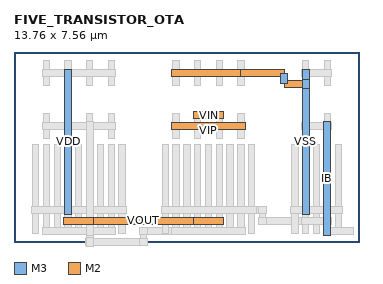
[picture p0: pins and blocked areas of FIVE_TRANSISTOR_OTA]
MACRO FIVE_TRANSISTOR_OTA
  ORIGIN 0 0 ;
  FOREIGN FIVE_TRANSISTOR_OTA 0 0 ;
  SIZE 13.76 BY 7.56 ;
  PIN IB
    DIRECTION INOUT ;
    USE SIGNAL ;
    PORT 
      LAYER M3 ;
        RECT 12.33 0.26 12.61 4.78 ;
    END
  END IB
  PIN VSS
    DIRECTION INOUT ;
    USE SIGNAL ;
    PORT 
      LAYER M2 ;
        RECT 6.28 6.58 9.2 6.86 ;
      LAYER M3 ;
        RECT 11.47 1.1 11.75 6.88 ;
      LAYER M2 ;
        RECT 9.03 6.58 10.75 6.86 ;
      LAYER M3 ;
        RECT 10.61 6.3 10.89 6.72 ;
      LAYER M2 ;
        RECT 10.75 6.16 11.61 6.44 ;
      LAYER M3 ;
        RECT 11.47 6.115 11.75 6.485 ;
    END
  END VSS
  PIN VOUT
    DIRECTION INOUT ;
    USE SIGNAL ;
    PORT 
      LAYER M2 ;
        RECT 1.98 0.7 3.18 0.98 ;
      LAYER M2 ;
        RECT 7.14 0.7 8.34 0.98 ;
      LAYER M2 ;
        RECT 3.01 0.7 7.31 0.98 ;
    END
  END VOUT
  PIN VDD
    DIRECTION INOUT ;
    USE SIGNAL ;
    PORT 
      LAYER M3 ;
        RECT 2.01 1.1 2.29 6.88 ;
    END
  END VDD
  PIN VIP
    DIRECTION INOUT ;
    USE SIGNAL ;
    PORT 
      LAYER M2 ;
        RECT 6.28 4.48 9.2 4.76 ;
    END
  END VIP
  PIN VIN
    DIRECTION INOUT ;
    USE SIGNAL ;
    PORT 
      LAYER M2 ;
        RECT 7.14 4.9 8.34 5.18 ;
    END
  END VIN
  OBS 
  LAYER M2 ;
        RECT 5.85 1.12 9.63 1.4 ;
  LAYER M2 ;
        RECT 11.44 0.7 12.64 0.98 ;
  LAYER M2 ;
        RECT 9.46 1.12 9.89 1.4 ;
  LAYER M1 ;
        RECT 9.765 0.84 10.015 1.26 ;
  LAYER M2 ;
        RECT 9.89 0.7 11.61 0.98 ;
  LAYER M1 ;
        RECT 9.765 0.755 10.015 0.925 ;
  LAYER M2 ;
        RECT 9.72 0.7 10.06 0.98 ;
  LAYER M1 ;
        RECT 9.765 1.175 10.015 1.345 ;
  LAYER M2 ;
        RECT 9.72 1.12 10.06 1.4 ;
  LAYER M1 ;
        RECT 9.765 0.755 10.015 0.925 ;
  LAYER M2 ;
        RECT 9.72 0.7 10.06 0.98 ;
  LAYER M1 ;
        RECT 9.765 1.175 10.015 1.345 ;
  LAYER M2 ;
        RECT 9.72 1.12 10.06 1.4 ;
  LAYER M3 ;
        RECT 2.87 0.26 3.15 4.78 ;
  LAYER M2 ;
        RECT 6.28 0.28 9.2 0.56 ;
  LAYER M3 ;
        RECT 2.87 0 3.15 0.42 ;
  LAYER M2 ;
        RECT 3.01 -0.14 5.16 0.14 ;
  LAYER M1 ;
        RECT 5.035 0 5.285 0.42 ;
  LAYER M2 ;
        RECT 5.16 0.28 6.45 0.56 ;
  LAYER M1 ;
        RECT 5.035 -0.085 5.285 0.085 ;
  LAYER M2 ;
        RECT 4.99 -0.14 5.33 0.14 ;
  LAYER M1 ;
        RECT 5.035 0.335 5.285 0.505 ;
  LAYER M2 ;
        RECT 4.99 0.28 5.33 0.56 ;
  LAYER M2 ;
        RECT 2.85 -0.14 3.17 0.14 ;
  LAYER M3 ;
        RECT 2.87 -0.16 3.15 0.16 ;
  LAYER M1 ;
        RECT 5.035 -0.085 5.285 0.085 ;
  LAYER M2 ;
        RECT 4.99 -0.14 5.33 0.14 ;
  LAYER M1 ;
        RECT 5.035 0.335 5.285 0.505 ;
  LAYER M2 ;
        RECT 4.99 0.28 5.33 0.56 ;
  LAYER M2 ;
        RECT 2.85 -0.14 3.17 0.14 ;
  LAYER M3 ;
        RECT 2.87 -0.16 3.15 0.16 ;
  LAYER M1 ;
        RECT 12.345 0.335 12.595 3.865 ;
  LAYER M1 ;
        RECT 12.345 4.115 12.595 5.125 ;
  LAYER M1 ;
        RECT 12.345 6.215 12.595 7.225 ;
  LAYER M1 ;
        RECT 12.775 0.335 13.025 3.865 ;
  LAYER M1 ;
        RECT 11.915 0.335 12.165 3.865 ;
  LAYER M1 ;
        RECT 11.485 0.335 11.735 3.865 ;
  LAYER M1 ;
        RECT 11.485 4.115 11.735 5.125 ;
  LAYER M1 ;
        RECT 11.485 6.215 11.735 7.225 ;
  LAYER M1 ;
        RECT 11.055 0.335 11.305 3.865 ;
  LAYER M2 ;
        RECT 12.3 0.28 13.5 0.56 ;
  LAYER M2 ;
        RECT 11.44 4.48 12.64 4.76 ;
  LAYER M2 ;
        RECT 11.01 1.12 13.07 1.4 ;
  LAYER M2 ;
        RECT 11.44 6.58 12.64 6.86 ;
  LAYER M3 ;
        RECT 12.33 0.26 12.61 4.78 ;
  LAYER M2 ;
        RECT 11.44 0.7 12.64 0.98 ;
  LAYER M3 ;
        RECT 11.47 1.1 11.75 6.88 ;
  LAYER M1 ;
        RECT 3.745 0.335 3.995 3.865 ;
  LAYER M1 ;
        RECT 3.745 4.115 3.995 5.125 ;
  LAYER M1 ;
        RECT 3.745 6.215 3.995 7.225 ;
  LAYER M1 ;
        RECT 4.175 0.335 4.425 3.865 ;
  LAYER M1 ;
        RECT 3.315 0.335 3.565 3.865 ;
  LAYER M1 ;
        RECT 2.885 0.335 3.135 3.865 ;
  LAYER M1 ;
        RECT 2.885 4.115 3.135 5.125 ;
  LAYER M1 ;
        RECT 2.885 6.215 3.135 7.225 ;
  LAYER M1 ;
        RECT 2.455 0.335 2.705 3.865 ;
  LAYER M1 ;
        RECT 2.025 0.335 2.275 3.865 ;
  LAYER M1 ;
        RECT 2.025 4.115 2.275 5.125 ;
  LAYER M1 ;
        RECT 2.025 6.215 2.275 7.225 ;
  LAYER M1 ;
        RECT 1.595 0.335 1.845 3.865 ;
  LAYER M1 ;
        RECT 1.165 0.335 1.415 3.865 ;
  LAYER M1 ;
        RECT 1.165 4.115 1.415 5.125 ;
  LAYER M1 ;
        RECT 1.165 6.215 1.415 7.225 ;
  LAYER M1 ;
        RECT 0.735 0.335 0.985 3.865 ;
  LAYER M2 ;
        RECT 1.12 0.28 4.04 0.56 ;
  LAYER M2 ;
        RECT 1.12 4.48 4.04 4.76 ;
  LAYER M2 ;
        RECT 0.69 1.12 4.47 1.4 ;
  LAYER M2 ;
        RECT 1.12 6.58 4.04 6.86 ;
  LAYER M3 ;
        RECT 2.87 0.26 3.15 4.78 ;
  LAYER M2 ;
        RECT 1.98 0.7 3.18 0.98 ;
  LAYER M3 ;
        RECT 2.01 1.1 2.29 6.88 ;
  LAYER M1 ;
        RECT 6.325 0.335 6.575 3.865 ;
  LAYER M1 ;
        RECT 6.325 4.115 6.575 5.125 ;
  LAYER M1 ;
        RECT 6.325 6.215 6.575 7.225 ;
  LAYER M1 ;
        RECT 5.895 0.335 6.145 3.865 ;
  LAYER M1 ;
        RECT 6.755 0.335 7.005 3.865 ;
  LAYER M1 ;
        RECT 7.185 0.335 7.435 3.865 ;
  LAYER M1 ;
        RECT 7.185 4.115 7.435 5.125 ;
  LAYER M1 ;
        RECT 7.185 6.215 7.435 7.225 ;
  LAYER M1 ;
        RECT 7.615 0.335 7.865 3.865 ;
  LAYER M1 ;
        RECT 8.045 0.335 8.295 3.865 ;
  LAYER M1 ;
        RECT 8.045 4.115 8.295 5.125 ;
  LAYER M1 ;
        RECT 8.045 6.215 8.295 7.225 ;
  LAYER M1 ;
        RECT 8.475 0.335 8.725 3.865 ;
  LAYER M1 ;
        RECT 8.905 0.335 9.155 3.865 ;
  LAYER M1 ;
        RECT 8.905 4.115 9.155 5.125 ;
  LAYER M1 ;
        RECT 8.905 6.215 9.155 7.225 ;
  LAYER M1 ;
        RECT 9.335 0.335 9.585 3.865 ;
  LAYER M2 ;
        RECT 6.28 6.58 9.2 6.86 ;
  LAYER M2 ;
        RECT 6.28 0.28 9.2 0.56 ;
  LAYER M2 ;
        RECT 7.14 0.7 8.34 0.98 ;
  LAYER M2 ;
        RECT 6.28 4.48 9.2 4.76 ;
  LAYER M2 ;
        RECT 7.14 4.9 8.34 5.18 ;
  LAYER M2 ;
        RECT 5.85 1.12 9.63 1.4 ;
  END 
END FIVE_TRANSISTOR_OTA
